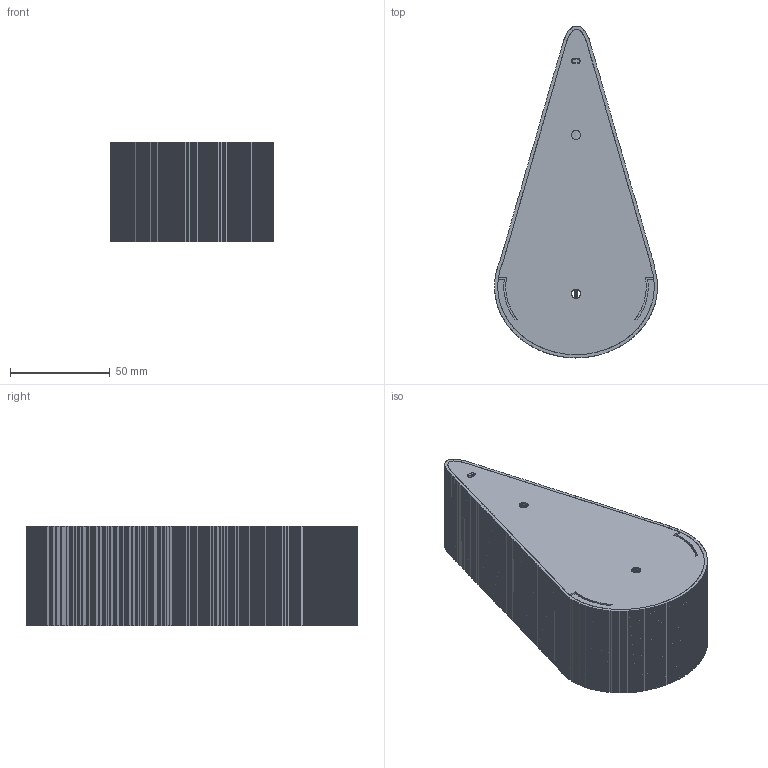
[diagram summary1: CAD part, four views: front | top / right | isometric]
STEP (ISO 10303-21) file: header records copied from the file, then geometry measured from it (millimetres).
FILE_DESCRIPTION(('Open CASCADE Model'),'2;1');
FILE_NAME('pinrose_unit_v5','2026-11-23T15:38:51',('Author'),( 'Open CASCADE'),'Open CASCADE STEP processor 8.0','build123d', 'Unknown');
FILE_SCHEMA(('AUTOMOTIVE_DESIGN { 1 0 10303 214 1 1 1 1 }'));
Length unit declared in the file: millimetre
Products named in the file (9): pinrose_unit_v5; pinrus_v5_cover; pinruswall_v5_bracket; motor_strap_v5_a; motor_strap_v5_b; pinruso_ring; motor_placeholder_D22x55; coupler_placeholder; crank_wire_placeholder
Assembly tree (8 placements, depth 2):
  pinrose_unit_v5
    pinrus_v5_cover
    pinruswall_v5_bracket
    motor_strap_v5_a
    motor_strap_v5_b
    pinruso_ring
    motor_placeholder_D22x55
    coupler_placeholder
    crank_wire_placeholder
Bounding box: 81.6 x 166.03 x 50 mm (x, y, z)
Volume: 107809.1 mm3; surface area: 86515 mm2
Topology: 8 solids, 8 shells, 7222 faces, 19078 edges, 11885 vertices
Faces by surface type: plane 7218, cylinder 4
Full cylindrical faces by diameter (mm): 4 x1, 7 x1, 10 x1, 22 x1
Entity records: 461294 total; most frequent: CARTESIAN_POINT 78596, DIRECTION 69458, LINE 54972, VECTOR 54972, ORIENTED_EDGE 38156, PCURVE 38156, DEFINITIONAL_REPRESENTATION 38156, EDGE_CURVE 19078
